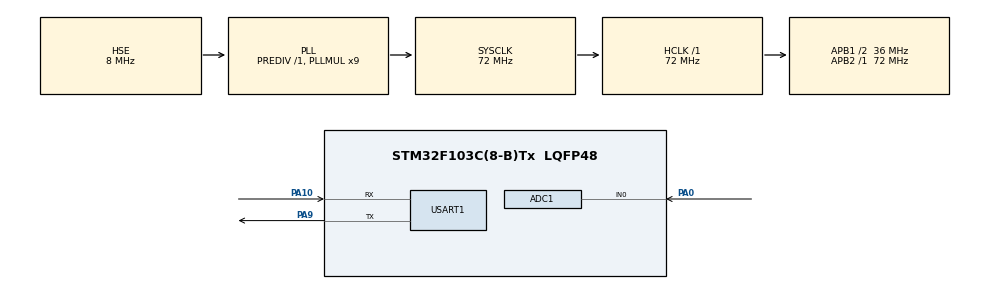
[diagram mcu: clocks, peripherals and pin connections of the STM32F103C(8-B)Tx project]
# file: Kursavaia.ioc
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ADC1.Channel-2\#ChannelRegularConversion=ADC_CHANNEL_0
ADC1.EnableAnalogWatchDog=true
ADC1.ExternalTrigConv=ADC_EXTERNALTRIGCONV_T3_TRGO
ADC1.NbrOfConversionFlag=1
ADC1.Rank-2\#ChannelRegularConversion=1
ADC1.SamplingTime-2\#ChannelRegularConversion=ADC_SAMPLETIME_13CYCLES_5
ADC1.master=1
Dma.ADC1.0.Direction=DMA_PERIPH_TO_MEMORY
Dma.ADC1.0.Instance=DMA1_Channel1
Dma.ADC1.0.MemDataAlignment=DMA_MDATAALIGN_HALFWORD
Dma.ADC1.0.MemInc=DMA_MINC_ENABLE
Dma.ADC1.0.Mode=DMA_NORMAL
Dma.ADC1.0.PeriphDataAlignment=DMA_PDATAALIGN_HALFWORD
Dma.ADC1.0.PeriphInc=DMA_PINC_DISABLE
Dma.ADC1.0.Priority=DMA_PRIORITY_LOW
Dma.Request0=ADC1
Mcu.Family=STM32F1
Mcu.Name=STM32F103C(8-B)Tx
Mcu.Package=LQFP48
NVIC.DMA1_Channel1_IRQn=true\:0\:0\:false\:false\:true\:false\:true\:true
NVIC.PriorityGroup=NVIC_PRIORITYGROUP_4
NVIC.TIM3_IRQn=true\:0\:0\:false\:false\:true\:true\:true\:true
NVIC.USART1_IRQn=true\:0\:0\:false\:false\:true\:true\:true\:true
PA0-WKUP.Signal=ADCx_IN0
PA10.Mode=Asynchronous
PA10.Signal=USART1_RX
PA13.Mode=Serial_Wire
PA13.Signal=SYS_JTMS-SWDIO
PA14.Mode=Serial_Wire
PA14.Signal=SYS_JTCK-SWCLK
PA9.Mode=Asynchronous
PA9.Signal=USART1_TX
PD0-OSC_IN.Mode=HSE-External-Oscillator
PD0-OSC_IN.Signal=RCC_OSC_IN
PD1-OSC_OUT.Mode=HSE-External-Oscillator
PD1-OSC_OUT.Signal=RCC_OSC_OUT
ProjectManager.HeapSize=0x200
ProjectManager.StackSize=0x400
ProjectManager.TargetToolchain=STM32CubeIDE
RCC.ADCPresc=RCC_ADCPCLK2_DIV6
RCC.AHBFreq_Value=72000000
RCC.APB1CLKDivider=RCC_HCLK_DIV2
RCC.APB1Freq_Value=36000000
RCC.APB1TimFreq_Value=72000000
RCC.APB2Freq_Value=72000000
RCC.APB2TimFreq_Value=72000000
RCC.HCLKFreq_Value=72000000
RCC.PLLMUL=RCC_PLL_MUL9
RCC.PLLSourceVirtual=RCC_PLLSOURCE_HSE
RCC.SYSCLKFreq_VALUE=72000000
RCC.SYSCLKSource=RCC_SYSCLKSOURCE_PLLCLK
RCC.USBFreq_Value=72000000
SH.ADCx_IN0.0=ADC1_IN0,IN0
TIM3.AutoReloadPreload=TIM_AUTORELOAD_PRELOAD_ENABLE
TIM3.Period=99
TIM3.Prescaler=1124
TIM3.TIM_MasterOutputTrigger=TIM_TRGO_UPDATE
USART1.VirtualMode=VM_ASYNC
VP_TIM3_VS_ClockSourceINT.Mode=Internal
board=custom

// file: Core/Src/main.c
/* USER CODE BEGIN Header */
/**
  ******************************************************************************
  * @file           : main.c
  * @brief          : Main program body
  ******************************************************************************
  * @attention
  *
  * Copyright (c) 2026 STMicroelectronics.
  * All rights reserved.
  *
  * This software is licensed under terms that can be found in the LICENSE file
  * in the root directory of this software component.
  * If no LICENSE file comes with this software, it is provided AS-IS.
  *
  ******************************************************************************
  */
/* USER CODE END Header */
#include "main.h"

/* USER CODE BEGIN Includes */
#include <stdio.h>
#include <string.h>
#include <math.h>

/* USER CODE END Includes */

/* USER CODE BEGIN PD */
#define ADC_REF         3.3f
#define ADC_MAX         4095.0f

#define DIVIDER_K       0.2233f

#define R1_LOAD         10.4f
#define R2_LOAD         2.6f

#define R0_INTERNAL     0.075f

#define NUM_POINTS      11
/* USER CODE END PD */

ADC_HandleTypeDef hadc1;
DMA_HandleTypeDef hdma_adc1;

TIM_HandleTypeDef htim3;

UART_HandleTypeDef huart1;

/* USER CODE BEGIN PV */
const float voltage_points[NUM_POINTS] =
{
    11.80f,
    11.90f,
    12.00f,
    12.10f,
    12.20f,
    12.30f,
    12.40f,
    12.50f,
    12.60f,
    12.70f,
    12.80f
};

const float soc_points[NUM_POINTS] =
{
     0,
    10,
    20,
    30,
    40,
    50,
    60,
    75,
    90,
    100,
    100
};
/* USER CODE END PV */

void SystemClock_Config(void);
static void MX_GPIO_Init(void);
static void MX_DMA_Init(void);
static void MX_ADC1_Init(void);
static void MX_TIM3_Init(void);
static void MX_USART1_UART_Init(void);
/* USER CODE BEGIN PFP */
float ADC_ToBatteryVoltage(uint16_t adc);
float MeasureVoltage(void);

float CalculateInternalResistance(float U1, float U2);
float CalculateSoH(float r);
/* USER CODE END PFP */

/* USER CODE BEGIN 0 */
int __io_putchar(int ch) {
    HAL_UART_Transmit(&huart1, (uint8_t*)&ch, 1, HAL_MAX_DELAY);
    return ch;
}

float getSOC(float voltage) {
    if (voltage <= voltage_points[0]) return 0.0f;
    if (voltage >= voltage_points[NUM_POINTS-1]) return 100.0f;
    for (int i = 0; i < NUM_POINTS-1; i++) {
        if (voltage >= voltage_points[i] && voltage <= voltage_points[i+1]) {
            float t = (voltage - voltage_points[i]) / (voltage_points[i+1] - voltage_points[i]);
            return soc_points[i] + t * (soc_points[i+1] - soc_points[i]);
        }
    }
    return 0.0f;
}

float ADC_ToBatteryVoltage(uint16_t adc)
{
    float v_adc =
        ((float)adc * ADC_REF) / ADC_MAX;

    return v_adc / DIVIDER_K;
}

float MeasureVoltage(void)
{
    uint32_t sum = 0;

    for(uint16_t i = 0; i < 256; i++)
    {
        HAL_ADC_Start(&hadc1);

        HAL_ADC_PollForConversion(&hadc1, 100);

        sum += HAL_ADC_GetValue(&hadc1);

        HAL_ADC_Stop(&hadc1);
    }

    uint16_t adc_avg = sum / 256;

    return ADC_ToBatteryVoltage(adc_avg);
}

float CalculateInternalResistance(float U1, float U2)
{
    float numerator =
        (U1 - U2) *
        R1_LOAD *
        R2_LOAD;

    float denominator =
        (U2 * R1_LOAD) -
        (U1 * R2_LOAD);

    if(fabsf(denominator) < 0.000001f)
        return -1.0f;

    return numerator / denominator;
}

float CalculateSoH(float r)
{
    float soh =
        (R0_INTERNAL / r) * 100.0f;

    if(soh > 100.0f)
        soh = 100.0f;

    if(soh < 0.0f)
        soh = 0.0f;

    return soh;
}
/* USER CODE END 0 */

int main(void)
{

  /* MCU Configuration--------------------------------------------------------*/

  /* Reset of all peripherals, Initializes the Flash interface and the Systick. */
  HAL_Init();

  /* Configure the system clock */
  SystemClock_Config();

  /* Initialize all configured peripherals */
  MX_GPIO_Init();
  MX_DMA_Init();
  MX_ADC1_Init();
  MX_TIM3_Init();
  MX_USART1_UART_Init();

  /* USER CODE BEGIN 2 */
  /* USER CODE BEGIN 2 */

  printf("Battery Analyzer Start\r\n");

  /* U0 */

  HAL_GPIO_WritePin(GPIOB,
                    GPIO_PIN_0 | GPIO_PIN_1,
                    GPIO_PIN_SET);

  HAL_Delay(100);

  float U0 = MeasureVoltage();

  /* U1 */

  HAL_GPIO_WritePin(GPIOB,
                    GPIO_PIN_1,
                    GPIO_PIN_RESET);

  HAL_Delay(100);

  float U1 = MeasureVoltage();

  HAL_GPIO_WritePin(GPIOB,
                    GPIO_PIN_1,
                    GPIO_PIN_SET);

  /* U2 */

  HAL_GPIO_WritePin(GPIOB,
                    GPIO_PIN_0,
                    GPIO_PIN_RESET);

  HAL_Delay(100);

  float U2 = MeasureVoltage();

  HAL_GPIO_WritePin(GPIOB,
                    GPIO_PIN_0,
                    GPIO_PIN_SET);

  /* Разлікі */

  float r =
      CalculateInternalResistance(U1, U2);

  float soc =
      getSOC(U0);

  float soh =
      CalculateSoH(r);

  /* Вывад */

  printf("U0 = %.2f V\r\n", U0);
  printf("U1 = %.2f V\r\n", U1);
  printf("U2 = %.2f V\r\n", U2);

  printf("Rint = %.4f Ohm\r\n", r);

  printf("SoC = %.1f %%\r\n", soc);

  printf("SoH = %.1f %%\r\n", soh);

  /* USER CODE END 2 */
  /* USER CODE END 2 */

  /* Infinite loop */
  while (1)
  {

    /* USER CODE BEGIN 3 */
	  HAL_PWR_EnterSLEEPMode(
	      PWR_MAINREGULATOR_ON,
	      PWR_SLEEPENTRY_WFI
	  );
  }
  /* USER CODE END 3 */
}

void SystemClock_Config(void)
{
  RCC_OscInitTypeDef RCC_OscInitStruct = {0};
  RCC_ClkInitTypeDef RCC_ClkInitStruct = {0};
  RCC_PeriphCLKInitTypeDef PeriphClkInit = {0};

  /** Initializes the RCC Oscillators according to the specified parameters
  * in the RCC_OscInitTypeDef structure.
  */
  RCC_OscInitStruct.OscillatorType = RCC_OSCILLATORTYPE_HSE;
  RCC_OscInitStruct.HSEState = RCC_HSE_ON;
  RCC_OscInitStruct.HSEPredivValue = RCC_HSE_PREDIV_DIV1;
  RCC_OscInitStruct.HSIState = RCC_HSI_ON;
  RCC_OscInitStruct.PLL.PLLState = RCC_PLL_ON;
  RCC_OscInitStruct.PLL.PLLSource = RCC_PLLSOURCE_HSE;
  RCC_OscInitStruct.PLL.PLLMUL = RCC_PLL_MUL9;
  if (HAL_RCC_OscConfig(&RCC_OscInitStruct) != HAL_OK)
  {
    Error_Handler();
  }

  /** Initializes the CPU, AHB and APB buses clocks
  */
  RCC_ClkInitStruct.ClockType = RCC_CLOCKTYPE_HCLK|RCC_CLOCKTYPE_SYSCLK
                              |RCC_CLOCKTYPE_PCLK1|RCC_CLOCKTYPE_PCLK2;
  RCC_ClkInitStruct.SYSCLKSource = RCC_SYSCLKSOURCE_PLLCLK;
  RCC_ClkInitStruct.AHBCLKDivider = RCC_SYSCLK_DIV1;
  RCC_ClkInitStruct.APB1CLKDivider = RCC_HCLK_DIV2;
  RCC_ClkInitStruct.APB2CLKDivider = RCC_HCLK_DIV1;

  if (HAL_RCC_ClockConfig(&RCC_ClkInitStruct, FLASH_LATENCY_2) != HAL_OK)
  {
    Error_Handler();
  }
  PeriphClkInit.PeriphClockSelection = RCC_PERIPHCLK_ADC;
  PeriphClkInit.AdcClockSelection = RCC_ADCPCLK2_DIV6;
  if (HAL_RCCEx_PeriphCLKConfig(&PeriphClkInit) != HAL_OK)
  {
    Error_Handler();
  }
}

static void MX_ADC1_Init(void)
{

  ADC_AnalogWDGConfTypeDef AnalogWDGConfig = {0};
  ADC_ChannelConfTypeDef sConfig = {0};

  /** Common config
  */
  hadc1.Instance = ADC1;
  hadc1.Init.ScanConvMode = ADC_SCAN_DISABLE;
  hadc1.Init.ContinuousConvMode = DISABLE;
  hadc1.Init.DiscontinuousConvMode = DISABLE;
  hadc1.Init.ExternalTrigConv = ADC_EXTERNALTRIGCONV_T3_TRGO;
  hadc1.Init.DataAlign = ADC_DATAALIGN_RIGHT;
  hadc1.Init.NbrOfConversion = 1;
  if (HAL_ADC_Init(&hadc1) != HAL_OK)
  {
    Error_Handler();
  }

  /** Configure Analog WatchDog 1
  */
  AnalogWDGConfig.WatchdogMode = ADC_ANALOGWATCHDOG_SINGLE_REG;
  AnalogWDGConfig.HighThreshold = 0;
  AnalogWDGConfig.LowThreshold = 0;
  AnalogWDGConfig.Channel = ADC_CHANNEL_0;
  AnalogWDGConfig.ITMode = DISABLE;
  if (HAL_ADC_AnalogWDGConfig(&hadc1, &AnalogWDGConfig) != HAL_OK)
  {
    Error_Handler();
  }

  /** Configure Regular Channel
  */
  sConfig.Channel = ADC_CHANNEL_0;
  sConfig.Rank = ADC_REGULAR_RANK_1;
  sConfig.SamplingTime = ADC_SAMPLETIME_13CYCLES_5;
  if (HAL_ADC_ConfigChannel(&hadc1, &sConfig) != HAL_OK)
  {
    Error_Handler();
  }

}

static void MX_TIM3_Init(void)
{

  TIM_ClockConfigTypeDef sClockSourceConfig = {0};
  TIM_MasterConfigTypeDef sMasterConfig = {0};

  htim3.Instance = TIM3;
  htim3.Init.Prescaler = 1124;
  htim3.Init.CounterMode = TIM_COUNTERMODE_UP;
  htim3.Init.Period = 99;
  htim3.Init.ClockDivision = TIM_CLOCKDIVISION_DIV1;
  htim3.Init.AutoReloadPreload = TIM_AUTORELOAD_PRELOAD_ENABLE;
  if (HAL_TIM_Base_Init(&htim3) != HAL_OK)
  {
    Error_Handler();
  }
  sClockSourceConfig.ClockSource = TIM_CLOCKSOURCE_INTERNAL;
  if (HAL_TIM_ConfigClockSource(&htim3, &sClockSourceConfig) != HAL_OK)
  {
    Error_Handler();
  }
  sMasterConfig.MasterOutputTrigger = TIM_TRGO_UPDATE;
  sMasterConfig.MasterSlaveMode = TIM_MASTERSLAVEMODE_DISABLE;
  if (HAL_TIMEx_MasterConfigSynchronization(&htim3, &sMasterConfig) != HAL_OK)
  {
    Error_Handler();
  }

}

static void MX_USART1_UART_Init(void)
{

  huart1.Instance = USART1;
  huart1.Init.BaudRate = 115200;
  huart1.Init.WordLength = UART_WORDLENGTH_8B;
  huart1.Init.StopBits = UART_STOPBITS_1;
  huart1.Init.Parity = UART_PARITY_NONE;
  huart1.Init.Mode = UART_MODE_TX_RX;
  huart1.Init.HwFlowCtl = UART_HWCONTROL_NONE;
  huart1.Init.OverSampling = UART_OVERSAMPLING_16;
  if (HAL_UART_Init(&huart1) != HAL_OK)
  {
    Error_Handler();
  }

}

static void MX_DMA_Init(void)
{

  /* DMA controller clock enable */
  __HAL_RCC_DMA1_CLK_ENABLE();

  /* DMA interrupt init */
  /* DMA1_Channel1_IRQn interrupt configuration */
  HAL_NVIC_SetPriority(DMA1_Channel1_IRQn, 0, 0);
  HAL_NVIC_EnableIRQ(DMA1_Channel1_IRQn);

}

static void MX_GPIO_Init(void)
{
  GPIO_InitTypeDef GPIO_InitStruct = {0};

  /* GPIO Ports Clock Enable */
  __HAL_RCC_GPIOD_CLK_ENABLE();
  __HAL_RCC_GPIOA_CLK_ENABLE();
  __HAL_RCC_GPIOB_CLK_ENABLE();

  /*Configure GPIO pin Output Level */
  HAL_GPIO_WritePin(GPIOB, GPIO_PIN_0|GPIO_PIN_1, GPIO_PIN_RESET);

  /*Configure GPIO pins : PB0 PB1 */
  GPIO_InitStruct.Pin = GPIO_PIN_0|GPIO_PIN_1;
  GPIO_InitStruct.Mode = GPIO_MODE_OUTPUT_PP;
  GPIO_InitStruct.Pull = GPIO_NOPULL;
  GPIO_InitStruct.Speed = GPIO_SPEED_FREQ_LOW;
  HAL_GPIO_Init(GPIOB, &GPIO_InitStruct);

}

void Error_Handler(void)
{
  __disable_irq();
  while (1)
  {
  }
}
